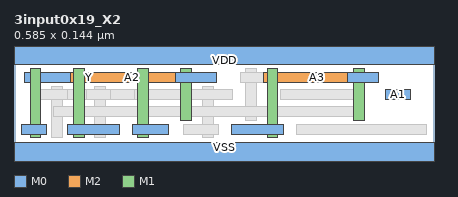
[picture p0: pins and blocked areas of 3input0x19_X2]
MACRO 3input0x19_X2
  CLASS CORE ;
  ORIGIN 0 0 ;
  FOREIGN 3input0x19_X2 0 0 ;
  SIZE 0.5850 BY 0.1440 ;
  SYMMETRY X Y ;
  SITE coresite ;
  PIN A1
    DIRECTION INPUT ;
    USE SIGNAL ;
    PORT
      LAYER M0 ;
        RECT 0.5175 0.0770 0.5520 0.0910 ;
    END
  END A1
  PIN A2
    DIRECTION INPUT ;
    USE SIGNAL ;
    PORT
      LAYER M2 ;
        RECT 0.0780 0.1010 0.2520 0.1150 ;
      LAYER M1 ;
        RECT 0.0825 0.0240 0.0975 0.1200 ;
        RECT 0.2325 0.0480 0.2475 0.1200 ;
      LAYER M0 ;
        RECT 0.2250 0.1010 0.2820 0.1150 ;
        RECT 0.0750 0.0290 0.1470 0.0430 ;
    END
  END A2
  PIN A3
    DIRECTION INPUT ;
    USE SIGNAL ;
    PORT
      LAYER M2 ;
        RECT 0.3480 0.1010 0.4950 0.1150 ;
      LAYER M1 ;
        RECT 0.3525 0.0240 0.3675 0.1200 ;
        RECT 0.4725 0.0480 0.4875 0.1200 ;
      LAYER M0 ;
        RECT 0.4650 0.1010 0.5070 0.1150 ;
        RECT 0.3030 0.0290 0.3750 0.0430 ;
    END
  END A3
  PIN Y
    DIRECTION OUTPUT ;
    USE SIGNAL ;
    PORT
      LAYER M1 ;
        RECT 0.0225 0.0240 0.0375 0.1200 ;
        RECT 0.1725 0.0240 0.1875 0.1200 ;
      LAYER M0 ;
        RECT 0.0150 0.1010 0.1950 0.1150 ;
        RECT 0.0105 0.0290 0.0450 0.0430 ;
        RECT 0.1650 0.0290 0.2145 0.0430 ;
    END
  END Y
  PIN VDD
    DIRECTION INOUT ;
    USE POWER ;
    SHAPE ABUTMENT ;
    PORT
      LAYER M0 ;
        RECT 0.0000 0.1260 0.5850 0.1620 ;
    END
  END VDD
  PIN VSS
    DIRECTION INOUT ;
    USE GROUND ;
    SHAPE ABUTMENT ;
    PORT
      LAYER M0 ;
        RECT 0.0000 -0.0180 0.5850 0.0180 ;
    END
  END VSS
  OBS
    LAYER M2 ;
      RECT 0.1080 0.0530 0.3420 0.0670 ;
      RECT 0.0450 0.0770 0.2820 0.0910 ;
    LAYER V1 ;
      RECT 0.0530 0.0770 0.0670 0.0910 ;
      RECT 0.2630 0.0770 0.2770 0.0910 ;
      RECT 0.0830 0.1010 0.0970 0.1150 ;
      RECT 0.2330 0.1010 0.2470 0.1150 ;
      RECT 0.1130 0.0530 0.1270 0.0670 ;
      RECT 0.3230 0.0530 0.3370 0.0670 ;
      RECT 0.3530 0.1010 0.3670 0.1150 ;
      RECT 0.4730 0.1010 0.4870 0.1150 ;
    LAYER M1 ;
      RECT 0.0525 0.0240 0.0675 0.0960 ;
      RECT 0.1125 0.0240 0.1275 0.0960 ;
      RECT 0.2625 0.0240 0.2775 0.0960 ;
      RECT 0.3225 0.0480 0.3375 0.1200 ;
    LAYER V0 ;
      RECT 0.0530 0.0770 0.0670 0.0910 ;
      RECT 0.2630 0.0770 0.2770 0.0910 ;
      RECT 0.2630 0.0290 0.2770 0.0430 ;
      RECT 0.0230 0.1010 0.0370 0.1150 ;
      RECT 0.0230 0.0290 0.0370 0.0430 ;
      RECT 0.1730 0.1010 0.1870 0.1150 ;
      RECT 0.1730 0.0290 0.1870 0.0430 ;
      RECT 0.0830 0.0290 0.0970 0.0430 ;
      RECT 0.2330 0.1010 0.2470 0.1150 ;
      RECT 0.1130 0.0770 0.1270 0.0910 ;
      RECT 0.3230 0.1010 0.3370 0.1150 ;
      RECT 0.3530 0.0290 0.3670 0.0430 ;
      RECT 0.4730 0.1010 0.4870 0.1150 ;
    LAYER M0 ;
      RECT 0.2355 0.0290 0.2850 0.0430 ;
      RECT 0.3930 0.0290 0.5745 0.0430 ;
      RECT 0.0555 0.0530 0.4845 0.0670 ;
      RECT 0.0330 0.0770 0.0750 0.0910 ;
      RECT 0.1005 0.0770 0.1350 0.0910 ;
      RECT 0.1680 0.0770 0.3045 0.0910 ;
      RECT 0.3705 0.0770 0.4845 0.0910 ;
      RECT 0.3150 0.1010 0.4395 0.1150 ;
  END
END 3input0x19_X2
